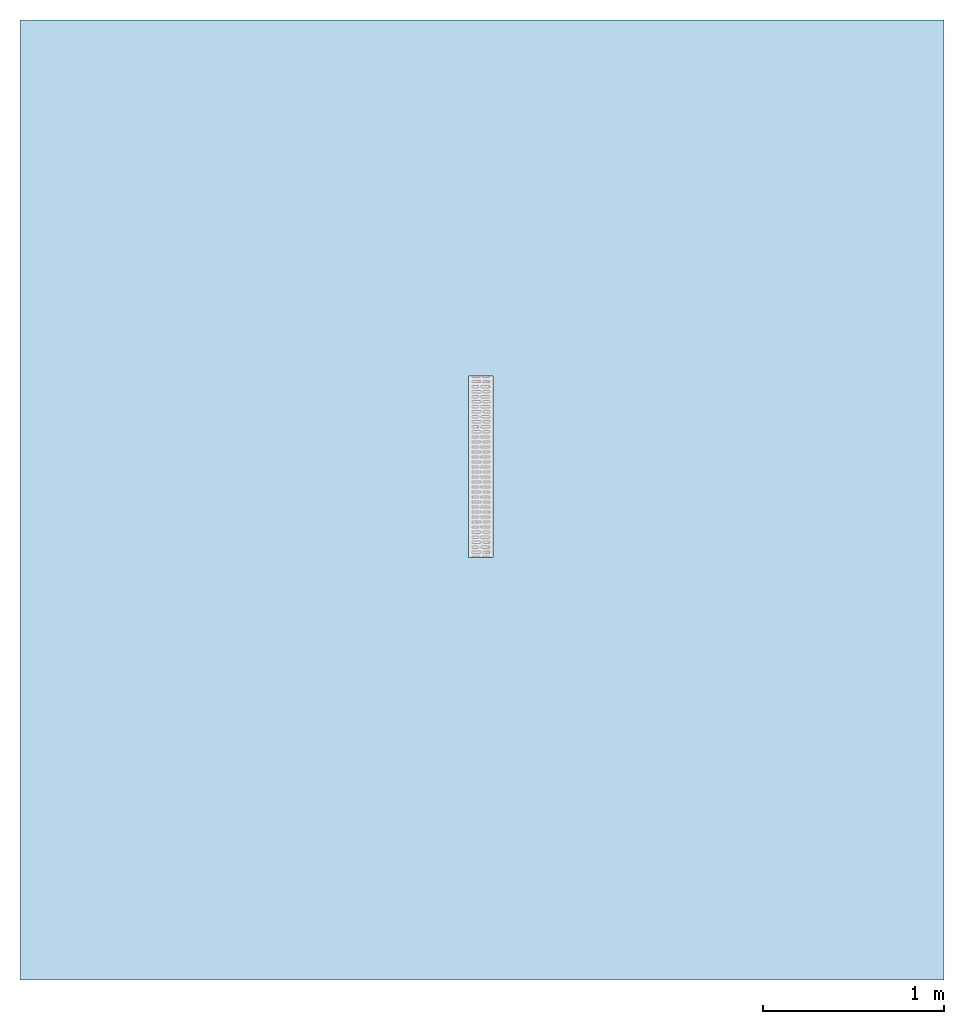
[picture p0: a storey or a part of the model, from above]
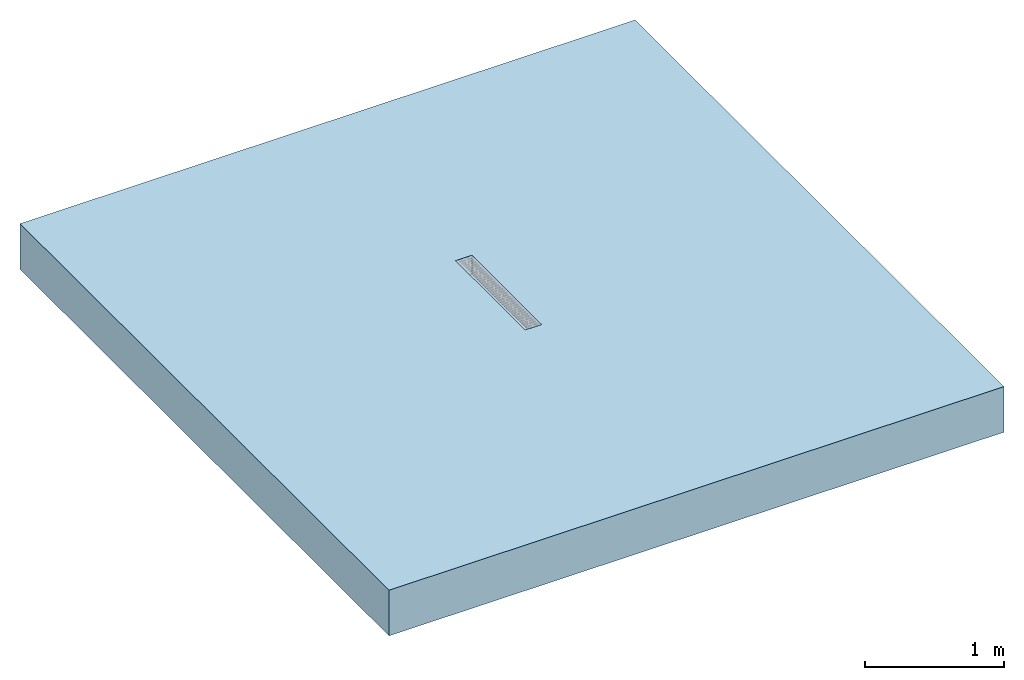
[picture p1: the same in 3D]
Properties of the parts of a building model (IFC2X3)

# File
Description: ViewDefinition [CoordinationView]
File name: 23003 - No 3 Sloping Channel - 1000mm LG - Invert Depth 140 145mm.ifc
Time: 2013-10-16T12:03:58
Written by: Autodesk Revit 2013
Made in: 20120221_2030(x64)

# IfcProject, Project Number
LongName: Project Name; Phase: Project Status

# IfcSite, Default
RefLatitude: 42, 21, 30, 344238; RefLongitude: -71, -3, -35, -194702; RefElevation: 0 mm

# IfcBuilding
Pset_BuildingCommon - NumberOfStoreys: 1
Other - Client Name: Owner; Project Address: ## Street City, State Zip; Project Name: Project Name; Project Issue Date: Issue Date; Project Number: Project Number; Project Status: Project Status

# IfcBuildingStorey, Level 1
LongName: Level 1; Elevation: 0 mm
Constraints - Elevation Base: 0; Elevation: 0 mm
Graphics - Symbol at End 1 Default: no; Symbol at End 2 Default: yes; Line Weight: 1; Color: 0; Line Pattern: Center; Symbol: M_Level Head - Circle: M_Level Head - Circle
Identity Data - Name: Level 1; Building Story: yes; Structural: no
Dimensions - Computation Height: 0 mm

# IfcBuildingElementProxy: 23003 - No 3 Sloping Channel - 1000mm LG - Invert Depth 140/145mm, Civil-Drainage-Channel-ACO-MultiDrain-M100D-Channel-System:23003 - No 3 Sloping Channel - 1000mm LG - Invert Depth 140/145mm:23003 - No 3 Sloping Channel - 1000mm LG - Invert Depth 140/145mm:1089344
In: Level 1
Material: Vienite® Synthetic Resin Concrete
Construction - 12673 - Grating - Intercept - Ductile Iron - 500mm Long: no; 12618 - Grating - Mesh - Galvanised Steel - 1000mm Long: no; 12656 - Grating - Perforated - Galvanised Steel - 1000mm long: no; 12680 - Grating - Heelguard™ - Composite Black - 500mm Long: no; 23404 - Universal Endcap - Male End: no; 12667 - Grating - Perforated - Galvanised Steel - 500mm Long: no; 12615 - Grating - Slotted - Galvanised Steel - 500mm Long: no; 23409 - Grating - ATec coated - Heelguard™ - Ductile Iron - 500mm Long: no; 12619 - Grating - Mesh - Galvanised Steel - 500mm Long: no; 12666 - Grating - Perforated - Galvanised Steel - 1000mm Long: no; 12614 - Grating - Slotted - Galvanised Steel - 1000mm Long: no; 12611 - Grating - Slotted - Galvanised Steel - 500mm Long: no; 23408 - Grating - Slotted - Ductile Iron - 500mm Long: no; 12657 - Grating - Perforated - Galvanised Steel - 500mm long: no; 23404 - Universal Endcap - Female End: no; 23405 - Grating - Heelguard™ - Ductile Iron - 500mm Long: no; 23406 - Grating - Solid Cover - Ductile Iron - 500mm Long: no; 12610 - Grating - Slotted - Galvanised Steel - 1000mm Long: no; 23453 - Kerb Outlet Bull Nose: no; 23451 - Downpipe connector 100mm Depth: no; Sloping Channel: yes; Constant Depth Junction Channel: no; Sump Unit: no; Grating 1000mm: yes; 23452 - Kerb Outlet Half Batter: no; Shallow Depth Channel: no; Constant Depth Channel: no; 23450 - Downpipe connector 75mm Depth: no; Shallow Depth Channel with seal: no
Dimensions - Length: 1000 mm; Volume: 10049468 mm3; Custom_Value_Length: 0 mm; FloorCut_Length: -1000 mm; EndCap Position: 1000 mm; Length Drain: -1000 mm; SlopingInvertDepth: 90 mm; SlopingOverallDepth: 160 mm; FloorCut_Depth: 165 mm; Endcap_Void_Depth: 0 mm; Depth: 150 mm; ShallowOverallDepth: 75 mm; EndCap_Female_Height: 160 mm; EndCap_Height: 165 mm; ShallowInvDepth: 55 mm; SlopingEndInvertDepth: 95 mm; InvDepth: 80 mm; FloorCut_Width: 135 mm; FloorCut_HorPosition: 67.5 mm; SlopingEndOverallDepth: 165 mm
Phasing - Phase Created: New Construction
Constraints - Level: Level: Level 1; Moves With Nearby Elements: no
Pset_BuildingElementProxyCommon - Reference: 23003 - No 3 Sloping Channel - 1000mm LG - Invert Depth 140/145mm
General - TagNumber: 0; SerialNumber: 0
Identity Data - Price: POA - contact ACO; Type Comments: ACO MultiDrain M100D No.3 Sloping Channel 1000mm Long; Address: ACO Business Park, Hitchin Road, Shefford, Bedfordshire, United Kingdom SG17 5TE; Product Page URL: http://www.aco.co.uk/product_detail.php?id=15; e-mail Sales: customersupport@aco.co.uk; Telephone: +44 (0)1462 816666; Maintenance guidelines: http://www.aco.co.uk/download.php?id=173; Fax: +44 (0)1462 815895; Installation guidelines: http://www.aco.co.uk/download.php?id=173; Watermark 1: This file is the property of ACO Technologies PLC; Model Description: Channel drainage system; Assembly Code: D2040; Watermark 2: This file is watermarked and users are prohibited to reproduce, adapt, distribute this information; Watermarked By: www.aco.co.uk; Cost: 0; Product Code: 23003; Assembly Description: Rain Water Drainage; Manufacturer: ACO Technologies plc - ACO Water Management Division; e-mail Technical: technical@aco.co.uk; Product brochure: http://www.aco.co.uk/download.php?id=173; Watermarked With: BIM Manager Premium Suite; URL: www.aco.co.uk; OmniClass Number: 23.70.50.24; Model: ACO MultiDrain MD - M100D; OmniClass Title: Rainwater Removal
Data - Pre-formed Outlet Ø: N/A; Concrete Surround Volume - Load Class A 15 - Concrete Pavement: N/A; Concrete Surround Volume - Load Class D 400 - Concrete Pavement: N/A; Hydraulic Performance: http://www.aco.co.uk/download.php?id=173; Invert Depth: 140mm/145mm; ACO Hydraulic Design Software: http://www.acodesign.co.uk; Channel C.S.A: N/A; Product Dimensions: 1000mm x 135mm x 160mm/165mm (LxWxH); Concrete Surround Volume - Load Class B 125 - C 250 - Concrete Pavement: N/A; Installation - Concrete Grade: Refer to brochure; Load Class: A 15 - D 400; Product Standard: BS EN 1433:2002, CE marked; Product Weight: 14.1 Kg
Model Properties - Grating Product code 12618: Load Class C250 - Meshed Galvanised Steel 410DL 1000mm long - 25x12mm slot - Intake Area 88000mm²/m - 3.1kg; Grating Product code 12667: Load Class A15 - Perforated Galvanised Steel 12667DL - 500mm long - 6mm hole - Intake Area 17800mm²/m - 1kg; Grating Product code 12611: Load Class A15 - Slotted Galvanised Steel 402DL - 500mm long - 10mm slot - Intake Area 31200mm²/m - 1kg; Grating Product code 12619: Load Class C250 - Meshed Steel 412DL 500mm long- 25x12mm slot - Intake Area 88000mm²/m - 1.5kg; Grating Product code 12656: Load Class C250 - Perforated Galvanised Steel 12656DL 1000mm long - 6mm hole - Intake Area 17800mm²/m - 4.8kg; Grating Product code 23405: Load Class D400 - Heelguard Ductile Iron 23405DL - 500mm long - 8mm slot - Intake Area 25400mm²/m - 4.2kg; Grating Product code 12680: Load Class C250 - Heelguard Composite Black 522DL - 500mm long - 8mm slot - Intake Area 14250mm²/m - 1.2kg; End Cap Product code 23404: No. 306 Universal End Cap - 135mm wide x 300mm long - Spigot Ø110mm x 50mm long - Silver - Polypropylene - 0.16kg; Grating Product code 12673: Load Class C250 - Intercept Ductile Iron 507DL - 500mm long - 31x12mm slot - Intake Area 43000mm²/m - 3.5kg; Grating Product code 23409: Load Class D400 - ATec coated Heelguard Ductile Iron 23409DL - 500mm long - 8mm slot - Intake Area 25400mm²/m - 4.2kg; Grating Product code 12615: Load Class C250 - Slotted Galvanised Steel 424DL 500mm long- 10mm slot - Intake Area 31200mm²/m - 2.2kg; Grating Product code 23408: Load Class D400 - Intercept Ductile Iron 507DL - 500mm long - 12mm slot - Intake Area 36200mm²/m - 3.8kg; Grating Product code 12657: Load Class C250 - Perforated Galvanised Steel 12657DL 500mm long- 6mm hole - Intake Area 17800mm²/m - 2.4kg; Grating Product code 23406: Load Class D400 - Solid Cover Ductile Iron 23406DL - 500mm long - 4.5kg; Grating Product code 12614: Load Class C250 - Slotted Galvanised Steel 423DL 1000mm long- 10mm slot - Intake Area 31200mm²/m - 4.3kg; Grating Product code 12610: Load Class A15 - Slotted Galvanised Steel 400DL - 1000mm long - 10mm slot - Intake Area 31200mm²/m - 2.2kg; Grating Product code 12666: Load Class A15 - Perforated Galvanised Steel 12666DL - 1000mm long - 6mm hole - Intake Area 17800mm²/m - 2.2kg
Materials and Finishes - Edge Rail Colour: Silver; Channel Colour: Brown; Edge Rail Material: Steel; Edge Rail Finish: Pre-galvanised; Channel Material: Vienite® Synthetic Resin Concrete
Green Building Properties - Edge Rail Recycled Material Content: Between 40% - 90%; Edge Rail Recyclable: Fully recyclable; Channel Recycled Material Content: 20% minimum; Channel Recyclable: Fully recyclable
Other - Revision: 1; CreatedBy: www.aco.co.uk

# IfcOpeningElement: Recess
In: Level 1
Constraints - Level: Level: Level 1; Related to Mass: no; Height Offset From Level: 0 mm; Room Bounding: yes
Dimensions - Volume: 10789725000 mm3; Thickness: 400 mm; Perimeter: 20800 mm; Area: 27030000 mm2
Structural - Enable Analytical Model: no; Structural: no
Phasing - Phase Created: New Construction
Analytical Properties - Roughness: 1; Absorptance: 0.1
Materials and Finishes - Structural Material: Plant
Construction - Function: 0; Default Thickness: 400 mm
Graphics - Coarse Scale Fill Color: 0

# IfcSlab: Floor:Generic Floor - 400mm, Floor:Generic Floor - 400mm:193825
In: Level 1
PredefinedType: FLOOR; Material: Plant 400 mm
Constraints - Level: Level: Level 1; Related to Mass: no; Height Offset From Level: 0 mm; Room Bounding: yes
Dimensions - Volume: 10789725000 mm3; Thickness: 400 mm; Perimeter: 20800 mm; Area: 27030000 mm2
Structural - Enable Analytical Model: no; Structural: no
Phasing - Phase Created: New Construction
Pset_SlabCommon - Reference: Generic Floor - 400mm; IsExternal: no; LoadBearing: yes
Analytical Properties - Roughness: 1; Absorptance: 0.1
Materials and Finishes - Structural Material: Plant
Construction - Function: 0; Default Thickness: 400 mm
Graphics - Coarse Scale Fill Color: 0
